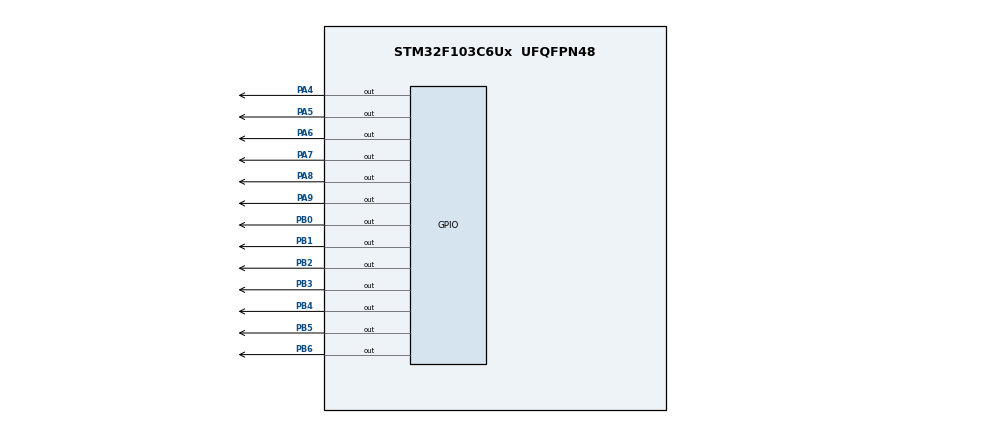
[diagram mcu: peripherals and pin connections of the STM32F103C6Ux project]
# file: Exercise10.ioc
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Mcu.Family=STM32F1
Mcu.Name=STM32F103C6Ux
Mcu.Package=UFQFPN48
NVIC.PriorityGroup=NVIC_PRIORITYGROUP_4
NVIC.TIM2_IRQn=true\:0\:0\:false\:false\:true\:true\:true\:true
PA4.Signal=GPIO_Output
PA5.Signal=GPIO_Output
PA6.Signal=GPIO_Output
PA7.Signal=GPIO_Output
PA8.Signal=GPIO_Output
PA9.Signal=GPIO_Output
PB0.Signal=GPIO_Output
PB1.Signal=GPIO_Output
PB2.Signal=GPIO_Output
PB3.Signal=GPIO_Output
PB4.Signal=GPIO_Output
PB5.Signal=GPIO_Output
PB6.Signal=GPIO_Output
ProjectManager.HeapSize=0x200
ProjectManager.StackSize=0x400
ProjectManager.TargetToolchain=STM32CubeIDE
RCC.APB1Freq_Value=8000000
RCC.APB2Freq_Value=8000000
TIM2.Period=9
TIM2.Prescaler=7999
VP_SYS_VS_ND.Mode=No_Debug
VP_TIM2_VS_ClockSourceINT.Mode=Internal
board=custom

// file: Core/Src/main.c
/* USER CODE BEGIN Header */
/**
  ******************************************************************************
  * @file           : main.c
  * @brief          : Main program body
  ******************************************************************************
  * @attention
  *
  * Copyright (c) 2025 STMicroelectronics.
  * All rights reserved.
  *
  * This software is licensed under terms that can be found in the LICENSE file
  * in the root directory of this software component.
  * If no LICENSE file comes with this software, it is provided AS-IS.
  *
  ******************************************************************************
  */
/* USER CODE END Header */
#include "main.h"

TIM_HandleTypeDef htim2;

void SystemClock_Config(void);
static void MX_GPIO_Init(void);
static void MX_TIM2_Init(void);
void updateClockBuffer(void);
void update7SEG(int index);
void updateLEDMatrix(int index);
void setTimer0(int duration);
void setTimer1(int duration);
void timer_run();

/* USER CODE BEGIN 0 */
int led_buffer[4] = {0, 0, 0, 0};
int hour = 15, minute = 8, second = 50;
int timer0_counter = 0;
int timer0_flag = 0;
int timer1_counter = 0;
int timer1_flag = 0;
int TIMER_CYCLE = 10;
int column_counter = 0;
int shift_counter = 0;
const int MAX_LED_MATRIX = 8;
int index_led_matrix = 0;
uint8_t matrix_buffer[8] = {0x00, 0x00, 0xFC, 0x12, 0x12, 0x12, 0xFC, 0x00};
/* USER CODE END 0 */

int main(void)
{

  /* MCU Configuration--------------------------------------------------------*/

  /* Reset of all peripherals, Initializes the Flash interface and the Systick. */
  HAL_Init();

  /* Configure the system clock */
  SystemClock_Config();

  /* Initialize all configured peripherals */
  MX_GPIO_Init();
  MX_TIM2_Init();
  /* USER CODE BEGIN 2 */
  HAL_TIM_Base_Start_IT(&htim2);
  /* USER CODE END 2 */
  int index_led = 0;
  updateClockBuffer();
  /* Infinite loop */
  /* USER CODE BEGIN WHILE */
  setTimer0(1000);
  setTimer1(250);
  update7SEG(index_led++);
  while (1)
  {
    /* USER CODE END WHILE */
	if(timer0_flag == 1){
		if(second >= 60){
			second = 0;
			minute++;
		}
		if(minute >= 60){
			minute = 0;
			hour++;
		}
		if(hour >= 24){
			hour = 0;
		}
		HAL_GPIO_TogglePin(GPIOA, GPIO_PIN_4);
		updateClockBuffer();
		setTimer0(1000);
		second++;
	}
	if(timer1_flag == 1){
		if(index_led > 3){
				index_led = 0;
		}
		update7SEG(index_led++);
		HAL_GPIO_TogglePin(GPIOA, GPIO_PIN_5);
		setTimer1(250);
	}

	if(column_counter >= 1000){
		if(index_led_matrix > 7){
			index_led_matrix = 0;
		}
		updateLEDMatrix(index_led_matrix++);
		shift_counter++;
		if(shift_counter == 30){
			uint8_t temp = matrix_buffer[0];
			for(uint8_t i = 1; i < 8; i++){
				matrix_buffer[i - 1] = matrix_buffer[i];
			}
			matrix_buffer[7] = temp;
			shift_counter = 0;
		}
		column_counter = 0;
	}
	column_counter++;
  }
}

void SystemClock_Config(void)
{
  RCC_OscInitTypeDef RCC_OscInitStruct = {0};
  RCC_ClkInitTypeDef RCC_ClkInitStruct = {0};

  /** Initializes the RCC Oscillators according to the specified parameters
  * in the RCC_OscInitTypeDef structure.
  */
  RCC_OscInitStruct.OscillatorType = RCC_OSCILLATORTYPE_HSI;
  RCC_OscInitStruct.HSIState = RCC_HSI_ON;
  RCC_OscInitStruct.HSICalibrationValue = RCC_HSICALIBRATION_DEFAULT;
  RCC_OscInitStruct.PLL.PLLState = RCC_PLL_NONE;
  if (HAL_RCC_OscConfig(&RCC_OscInitStruct) != HAL_OK)
  {
    Error_Handler();
  }

  /** Initializes the CPU, AHB and APB buses clocks
  */
  RCC_ClkInitStruct.ClockType = RCC_CLOCKTYPE_HCLK|RCC_CLOCKTYPE_SYSCLK
                              |RCC_CLOCKTYPE_PCLK1|RCC_CLOCKTYPE_PCLK2;
  RCC_ClkInitStruct.SYSCLKSource = RCC_SYSCLKSOURCE_HSI;
  RCC_ClkInitStruct.AHBCLKDivider = RCC_SYSCLK_DIV1;
  RCC_ClkInitStruct.APB1CLKDivider = RCC_HCLK_DIV1;
  RCC_ClkInitStruct.APB2CLKDivider = RCC_HCLK_DIV1;

  if (HAL_RCC_ClockConfig(&RCC_ClkInitStruct, FLASH_LATENCY_0) != HAL_OK)
  {
    Error_Handler();
  }
}

static void MX_TIM2_Init(void)
{

  TIM_ClockConfigTypeDef sClockSourceConfig = {0};
  TIM_MasterConfigTypeDef sMasterConfig = {0};

  htim2.Instance = TIM2;
  htim2.Init.Prescaler = 7999;
  htim2.Init.CounterMode = TIM_COUNTERMODE_UP;
  htim2.Init.Period = 9;
  htim2.Init.ClockDivision = TIM_CLOCKDIVISION_DIV1;
  htim2.Init.AutoReloadPreload = TIM_AUTORELOAD_PRELOAD_DISABLE;
  if (HAL_TIM_Base_Init(&htim2) != HAL_OK)
  {
    Error_Handler();
  }
  sClockSourceConfig.ClockSource = TIM_CLOCKSOURCE_INTERNAL;
  if (HAL_TIM_ConfigClockSource(&htim2, &sClockSourceConfig) != HAL_OK)
  {
    Error_Handler();
  }
  sMasterConfig.MasterOutputTrigger = TIM_TRGO_RESET;
  sMasterConfig.MasterSlaveMode = TIM_MASTERSLAVEMODE_DISABLE;
  if (HAL_TIMEx_MasterConfigSynchronization(&htim2, &sMasterConfig) != HAL_OK)
  {
    Error_Handler();
  }

}

static void MX_GPIO_Init(void)
{
  GPIO_InitTypeDef GPIO_InitStruct = {0};

  /* GPIO Ports Clock Enable */
  __HAL_RCC_GPIOA_CLK_ENABLE();
  __HAL_RCC_GPIOB_CLK_ENABLE();

  /*Configure GPIO pin Output Level */
  HAL_GPIO_WritePin(GPIOA, GPIO_PIN_2|GPIO_PIN_3|GPIO_PIN_4|GPIO_PIN_5|GPIO_PIN_6|GPIO_PIN_7
                          |GPIO_PIN_8|GPIO_PIN_9|GPIO_PIN_10|GPIO_PIN_11|GPIO_PIN_12|GPIO_PIN_13
						  |GPIO_PIN_14|GPIO_PIN_15, GPIO_PIN_RESET);

  /*Configure GPIO pin Output Level */
  HAL_GPIO_WritePin(GPIOB, GPIO_PIN_0|GPIO_PIN_1|GPIO_PIN_2|GPIO_PIN_3
                          |GPIO_PIN_4|GPIO_PIN_5|GPIO_PIN_6|GPIO_PIN_8
						  |GPIO_PIN_9|GPIO_PIN_10|GPIO_PIN_11|GPIO_PIN_12
						  |GPIO_PIN_13|GPIO_PIN_14|GPIO_PIN_15, GPIO_PIN_RESET);

  /*Configure GPIO pins : PA4 PA5 PA6 PA7
                           PA8 PA9 */
  GPIO_InitStruct.Pin = GPIO_PIN_2|GPIO_PIN_3|GPIO_PIN_4|GPIO_PIN_5|GPIO_PIN_6|GPIO_PIN_7
          	  	  	  	|GPIO_PIN_8|GPIO_PIN_9|GPIO_PIN_10|GPIO_PIN_11|GPIO_PIN_12|GPIO_PIN_13
						|GPIO_PIN_14|GPIO_PIN_15;
  GPIO_InitStruct.Mode = GPIO_MODE_OUTPUT_PP;
  GPIO_InitStruct.Pull = GPIO_NOPULL;
  GPIO_InitStruct.Speed = GPIO_SPEED_FREQ_LOW;
  HAL_GPIO_Init(GPIOA, &GPIO_InitStruct);

  /*Configure GPIO pins : PB0 PB1 PB2 PB3
                           PB4 PB5 PB6 */
  GPIO_InitStruct.Pin = GPIO_PIN_0|GPIO_PIN_1|GPIO_PIN_2|GPIO_PIN_3
          	  	  	  	|GPIO_PIN_4|GPIO_PIN_5|GPIO_PIN_6|GPIO_PIN_8
						|GPIO_PIN_9|GPIO_PIN_10|GPIO_PIN_11|GPIO_PIN_12
						|GPIO_PIN_13|GPIO_PIN_14|GPIO_PIN_15;
  GPIO_InitStruct.Mode = GPIO_MODE_OUTPUT_PP;
  GPIO_InitStruct.Pull = GPIO_NOPULL;
  GPIO_InitStruct.Speed = GPIO_SPEED_FREQ_LOW;
  HAL_GPIO_Init(GPIOB, &GPIO_InitStruct);

}

/* USER CODE BEGIN 4 */
void updateClockBuffer(void){
	led_buffer[0] = hour / 10; //extract hour second digit
	led_buffer[1] = hour % 10; //extract hour first digit
	led_buffer[2] = minute / 10; //extract minute second digit
	led_buffer[3] = minute % 10; //extract minute first digit
}
void display7SEG(int num){
  switch(num){
      case 0:
          HAL_GPIO_WritePin(GPIOB, GPIO_PIN_0 | GPIO_PIN_1 | GPIO_PIN_2 | GPIO_PIN_3 | GPIO_PIN_4 | GPIO_PIN_5, RESET);
          HAL_GPIO_WritePin(GPIOB,  GPIO_PIN_6, SET);
          break;
      case 1:
          HAL_GPIO_WritePin(GPIOB, GPIO_PIN_1 | GPIO_PIN_2, RESET);
          HAL_GPIO_WritePin(GPIOB,  GPIO_PIN_0 | GPIO_PIN_3 | GPIO_PIN_4 | GPIO_PIN_5 | GPIO_PIN_6, SET);
          break;
      case 2:
          HAL_GPIO_WritePin(GPIOB, GPIO_PIN_0 | GPIO_PIN_1 | GPIO_PIN_3 | GPIO_PIN_4 | GPIO_PIN_6, RESET);
          HAL_GPIO_WritePin(GPIOB,  GPIO_PIN_2 | GPIO_PIN_5, SET);
          break;
      case 3:
          HAL_GPIO_WritePin(GPIOB, GPIO_PIN_0 | GPIO_PIN_1 | GPIO_PIN_3 | GPIO_PIN_2 | GPIO_PIN_6, RESET);
          HAL_GPIO_WritePin(GPIOB,  GPIO_PIN_4 | GPIO_PIN_5, SET);
          break;
      case 4:
          HAL_GPIO_WritePin(GPIOB, GPIO_PIN_1 | GPIO_PIN_2 | GPIO_PIN_5 | GPIO_PIN_6, RESET);
          HAL_GPIO_WritePin(GPIOB,  GPIO_PIN_0 | GPIO_PIN_3 | GPIO_PIN_4, SET);
          break;
      case 5:
          HAL_GPIO_WritePin(GPIOB, GPIO_PIN_0 | GPIO_PIN_5 | GPIO_PIN_3 | GPIO_PIN_2 | GPIO_PIN_6, RESET);
          HAL_GPIO_WritePin(GPIOB,  GPIO_PIN_4 | GPIO_PIN_1, SET);
          break;
      case 6:
          HAL_GPIO_WritePin(GPIOB, GPIO_PIN_0 | GPIO_PIN_5 | GPIO_PIN_3 | GPIO_PIN_4 | GPIO_PIN_2 | GPIO_PIN_6, RESET);
          HAL_GPIO_WritePin(GPIOB, GPIO_PIN_1, SET);
          break;
      case 7:
          HAL_GPIO_WritePin(GPIOB, GPIO_PIN_0 | GPIO_PIN_1 | GPIO_PIN_2, RESET);
          HAL_GPIO_WritePin(GPIOB, GPIO_PIN_3 | GPIO_PIN_4 | GPIO_PIN_5 | GPIO_PIN_6, SET);
          break;
      case 8:
          HAL_GPIO_WritePin(GPIOB, GPIO_PIN_0 | GPIO_PIN_1 | GPIO_PIN_2 | GPIO_PIN_3 | GPIO_PIN_4 | GPIO_PIN_5 | GPIO_PIN_6, RESET);
          break;
      case 9:
          HAL_GPIO_WritePin(GPIOB, GPIO_PIN_0 | GPIO_PIN_1 | GPIO_PIN_2 | GPIO_PIN_3 | GPIO_PIN_5 | GPIO_PIN_6, RESET);
          HAL_GPIO_WritePin(GPIOB, GPIO_PIN_4, SET);
          break;
      default:
          HAL_GPIO_WritePin(GPIOB, GPIO_PIN_0 | GPIO_PIN_1 | GPIO_PIN_2 | GPIO_PIN_3 | GPIO_PIN_4 | GPIO_PIN_5 | GPIO_PIN_6, SET);
          break;
  }
}

const int MAX_LED = 4;

void update7SEG(int index){
	switch(index){
		case 0:
			HAL_GPIO_WritePin(GPIOA, GPIO_PIN_6, GPIO_PIN_RESET);
			HAL_GPIO_WritePin(GPIOA, GPIO_PIN_7 | GPIO_PIN_8 | GPIO_PIN_9, GPIO_PIN_SET);
			display7SEG(led_buffer[0]);
			break;
		case 1:
			HAL_GPIO_WritePin(GPIOA, GPIO_PIN_7, GPIO_PIN_RESET);
			HAL_GPIO_WritePin(GPIOA, GPIO_PIN_6 | GPIO_PIN_8 | GPIO_PIN_9, GPIO_PIN_SET);
			display7SEG(led_buffer[1]);
			break;
		case 2:
			HAL_GPIO_WritePin(GPIOA, GPIO_PIN_8, GPIO_PIN_RESET);
			HAL_GPIO_WritePin(GPIOA, GPIO_PIN_6 | GPIO_PIN_7 | GPIO_PIN_9, GPIO_PIN_SET);
			display7SEG(led_buffer[2]);
			break;
		case 3:
			HAL_GPIO_WritePin(GPIOA, GPIO_PIN_9, GPIO_PIN_RESET);
			HAL_GPIO_WritePin(GPIOA, GPIO_PIN_6 | GPIO_PIN_7 | GPIO_PIN_8, GPIO_PIN_SET);
			display7SEG(led_buffer[3]);
			break;
		default:
			break;
	}
}

void HAL_TIM_PeriodElapsedCallback(TIM_HandleTypeDef *htim){
	timer_run();
}

void setTimer0(int duration){
	timer0_counter = duration / TIMER_CYCLE;
	timer0_flag = 0;
}

void setTimer1(int duration){
	timer1_counter = duration / TIMER_CYCLE;
	timer1_flag = 0;
}

void timer_run(){
	if(timer0_counter > 0){
		timer0_counter--;
		if(timer0_counter == 0) timer0_flag = 1;
	}
	if(timer1_counter > 0){
		timer1_counter--;
		if(timer1_counter == 0) timer1_flag = 1;
	}
}

void updateLEDMatrix(int index){
	HAL_GPIO_WritePin(GPIOA, GPIO_PIN_2 | GPIO_PIN_3 | GPIO_PIN_10 | GPIO_PIN_11 | GPIO_PIN_12 | GPIO_PIN_13 | GPIO_PIN_14 | GPIO_PIN_15, GPIO_PIN_SET);
	for(uint8_t i = 0; i < 8; i++){
		HAL_GPIO_WritePin(GPIOB, GPIO_PIN_8 << i, (matrix_buffer[index] & (1 << i)) ? GPIO_PIN_RESET : GPIO_PIN_SET);
	}
	switch(index){
		case 0:
			HAL_GPIO_WritePin(GPIOA, GPIO_PIN_2, GPIO_PIN_RESET);
			break;
		case 1:
			HAL_GPIO_WritePin(GPIOA, GPIO_PIN_3, GPIO_PIN_RESET);
			break;
		case 2:
			HAL_GPIO_WritePin(GPIOA, GPIO_PIN_10, GPIO_PIN_RESET);
			break;
		case 3:
			HAL_GPIO_WritePin(GPIOA, GPIO_PIN_11, GPIO_PIN_RESET);
			break;
		case 4:
			HAL_GPIO_WritePin(GPIOA, GPIO_PIN_12, GPIO_PIN_RESET);
			break;
		case 5:
			HAL_GPIO_WritePin(GPIOA, GPIO_PIN_13, GPIO_PIN_RESET);
			break;
		case 6:
			HAL_GPIO_WritePin(GPIOA, GPIO_PIN_14, GPIO_PIN_RESET);
			break;
		case 7:
			HAL_GPIO_WritePin(GPIOA, GPIO_PIN_15, GPIO_PIN_RESET);
			break;
		default:
			HAL_GPIO_WritePin(GPIOA, GPIO_PIN_2 | GPIO_PIN_3 | GPIO_PIN_10 | GPIO_PIN_11 | GPIO_PIN_12 | GPIO_PIN_13 | GPIO_PIN_14 | GPIO_PIN_15, GPIO_PIN_SET);
			break;
	}
}

/* USER CODE END 4 */

void Error_Handler(void)
{
  __disable_irq();
  while (1)
  {
  }
}
